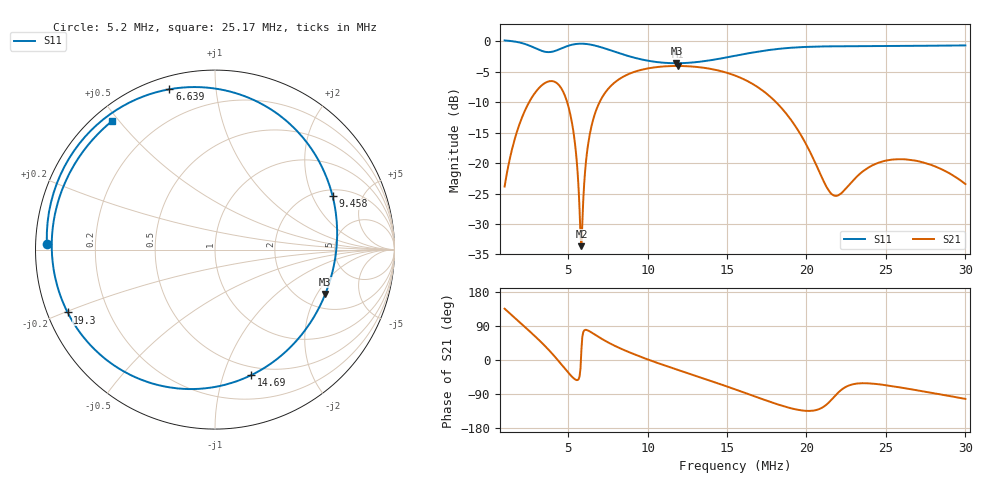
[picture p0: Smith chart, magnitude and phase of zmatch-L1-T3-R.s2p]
# HZ S RI R 50
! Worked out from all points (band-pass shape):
!   505 points, 1 MHz to 30 MHz, reference 50 ohm
!   highest |S21| = -4.02 dB at 11.93 MHz (marker M1); lowest = -33.6 dB at 5.833 MHz (marker M2)
!   |S21| within 3 dB of the highest: 3.428 MHz to 4.365 MHz (937.2 kHz wide, 24 % of centre); 7.802 MHz to 16.64 MHz (8.835 MHz wide, 72.3 % of centre)
!   lowest |S11| = -3.6 dB at 11.82 MHz (marker M3), VSWR 4.93, Z = 134 - j118 ohm
!   |S11| at or under -10 dB: nowhere
!   S12 and S22 are empty: the file has one direction only
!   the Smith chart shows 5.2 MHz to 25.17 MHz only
!   S11 on the Smith chart (normalised r, x): 5.2 MHz: 0.03, +0.02; 6.639 MHz: 0.06, +0.75; 9.458 MHz: 2.33, +2.87; 14.69 MHz: 0.42, -1.24; 19.3 MHz: 0.06, -0.20; 25.17 MHz: 0.05, +0.48
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1000000  -0.6154 0.8128  -0.0458 0.0452  0 0  0 0
2093260  0.3217 0.9149  -0.0166 0.2365  0 0  0 0
3071440  0.8641 7.53e-05  0.2224 0.3346  0 0  0 0
3646840  0.4934 -0.6537  0.3912 0.2486  0 0  0 0
4049620  -0.0207 -0.8264  0.4567 0.115  0 0  0 0
4682560  -0.7346 -0.5002  0.3698 -0.1148  0 0  0 0
5200420  -0.937 0.0337  0.1688 -0.1541  0 0  0 0
5833360  -0.7556 0.5909  0.0186 0.00926  0 0  0 0
6178600  -0.5516 0.7766  0.0228 0.118  0 0  0 0
6638920  -0.2535 0.8934  0.0909 0.2266  0 0  0 0
7962340  0.3917 0.7224  0.3716 0.2784  0 0  0 0
9458380  0.6555 0.2965  0.569 0.102  0 0  0 0
1.066672e7  0.6754 -0.00509  0.611 -0.0908  0 0  0 0
1.181752e7  0.6145 -0.2475  0.5707 -0.2651  0 0  0 0
1.19326e7  0.6052 -0.2701  0.563 -0.2812  0 0  0 0
1.469452e7  0.2002 -0.7002  0.2353 -0.516  0 0  0 0
1.550008e7  0.0143 -0.7625  0.1151 -0.5122  0 0  0 0
1.929772e7  -0.8212 -0.3504  -0.1297 -0.1541  0 0  0 0
2.033344e7  -0.8992 -0.1097  -0.0803 -0.0831  0 0  0 0
2.182948e7  -0.8871 0.2185  -0.00301 -0.0538  0 0  0 0
2.51668e7  -0.5765 0.7139  0.0405 -0.0978  0 0  0 0
3.000016e7  0.0123 0.9281  -0.0148 -0.0656  0 0  0 0
